# Generated by FakeRAM 2.0
VERSION 5.7 ;
BUSBITCHARS "[]" ;
PROPERTYDEFINITIONS
  MACRO width INTEGER ;
  MACRO depth INTEGER ;
  MACRO banks INTEGER ;
END PROPERTYDEFINITIONS
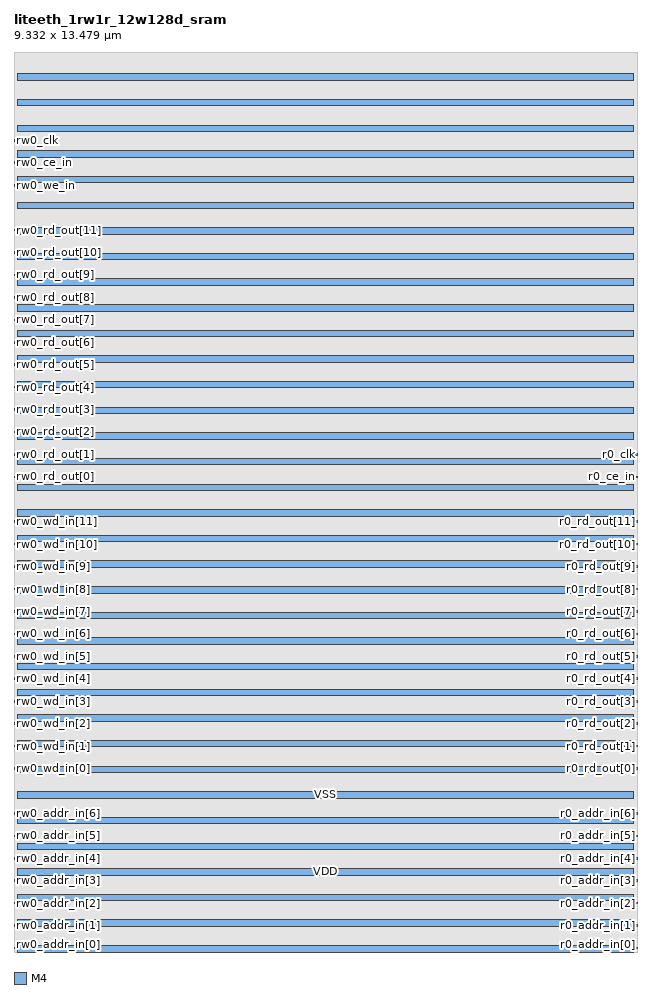
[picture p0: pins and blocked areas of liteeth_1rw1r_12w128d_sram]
MACRO liteeth_1rw1r_12w128d_sram
  PROPERTY width 12 ;
  PROPERTY depth 128 ;
  PROPERTY banks 1 ;
  FOREIGN liteeth_1rw1r_12w128d_sram 0 0 ;
  SYMMETRY X Y R90 ;
  SIZE 9.332 BY 13.479 ;
  CLASS BLOCK ;
  PIN r0_addr_in[0]
    DIRECTION INPUT ;
    USE SIGNAL ;
    SHAPE ABUTMENT ;
    PORT
      LAYER M4 ;
      RECT 9.308 0.048 9.332 0.072 ;
    END
  END r0_addr_in[0]
  PIN r0_addr_in[1]
    DIRECTION INPUT ;
    USE SIGNAL ;
    SHAPE ABUTMENT ;
    PORT
      LAYER M4 ;
      RECT 9.308 0.384 9.332 0.408 ;
    END
  END r0_addr_in[1]
  PIN r0_addr_in[2]
    DIRECTION INPUT ;
    USE SIGNAL ;
    SHAPE ABUTMENT ;
    PORT
      LAYER M4 ;
      RECT 9.308 0.720 9.332 0.744 ;
    END
  END r0_addr_in[2]
  PIN r0_addr_in[3]
    DIRECTION INPUT ;
    USE SIGNAL ;
    SHAPE ABUTMENT ;
    PORT
      LAYER M4 ;
      RECT 9.308 1.056 9.332 1.080 ;
    END
  END r0_addr_in[3]
  PIN r0_addr_in[4]
    DIRECTION INPUT ;
    USE SIGNAL ;
    SHAPE ABUTMENT ;
    PORT
      LAYER M4 ;
      RECT 9.308 1.392 9.332 1.416 ;
    END
  END r0_addr_in[4]
  PIN r0_addr_in[5]
    DIRECTION INPUT ;
    USE SIGNAL ;
    SHAPE ABUTMENT ;
    PORT
      LAYER M4 ;
      RECT 9.308 1.728 9.332 1.752 ;
    END
  END r0_addr_in[5]
  PIN r0_addr_in[6]
    DIRECTION INPUT ;
    USE SIGNAL ;
    SHAPE ABUTMENT ;
    PORT
      LAYER M4 ;
      RECT 9.308 2.064 9.332 2.088 ;
    END
  END r0_addr_in[6]
  PIN r0_rd_out[0]
    DIRECTION OUTPUT ;
    USE SIGNAL ;
    SHAPE ABUTMENT ;
    PORT
      LAYER M4 ;
      RECT 9.308 2.736 9.332 2.760 ;
    END
  END r0_rd_out[0]
  PIN r0_rd_out[1]
    DIRECTION OUTPUT ;
    USE SIGNAL ;
    SHAPE ABUTMENT ;
    PORT
      LAYER M4 ;
      RECT 9.308 3.072 9.332 3.096 ;
    END
  END r0_rd_out[1]
  PIN r0_rd_out[2]
    DIRECTION OUTPUT ;
    USE SIGNAL ;
    SHAPE ABUTMENT ;
    PORT
      LAYER M4 ;
      RECT 9.308 3.408 9.332 3.432 ;
    END
  END r0_rd_out[2]
  PIN r0_rd_out[3]
    DIRECTION OUTPUT ;
    USE SIGNAL ;
    SHAPE ABUTMENT ;
    PORT
      LAYER M4 ;
      RECT 9.308 3.744 9.332 3.768 ;
    END
  END r0_rd_out[3]
  PIN r0_rd_out[4]
    DIRECTION OUTPUT ;
    USE SIGNAL ;
    SHAPE ABUTMENT ;
    PORT
      LAYER M4 ;
      RECT 9.308 4.080 9.332 4.104 ;
    END
  END r0_rd_out[4]
  PIN r0_rd_out[5]
    DIRECTION OUTPUT ;
    USE SIGNAL ;
    SHAPE ABUTMENT ;
    PORT
      LAYER M4 ;
      RECT 9.308 4.416 9.332 4.440 ;
    END
  END r0_rd_out[5]
  PIN r0_rd_out[6]
    DIRECTION OUTPUT ;
    USE SIGNAL ;
    SHAPE ABUTMENT ;
    PORT
      LAYER M4 ;
      RECT 9.308 4.752 9.332 4.776 ;
    END
  END r0_rd_out[6]
  PIN r0_rd_out[7]
    DIRECTION OUTPUT ;
    USE SIGNAL ;
    SHAPE ABUTMENT ;
    PORT
      LAYER M4 ;
      RECT 9.308 5.088 9.332 5.112 ;
    END
  END r0_rd_out[7]
  PIN r0_rd_out[8]
    DIRECTION OUTPUT ;
    USE SIGNAL ;
    SHAPE ABUTMENT ;
    PORT
      LAYER M4 ;
      RECT 9.308 5.424 9.332 5.448 ;
    END
  END r0_rd_out[8]
  PIN r0_rd_out[9]
    DIRECTION OUTPUT ;
    USE SIGNAL ;
    SHAPE ABUTMENT ;
    PORT
      LAYER M4 ;
      RECT 9.308 5.760 9.332 5.784 ;
    END
  END r0_rd_out[9]
  PIN r0_rd_out[10]
    DIRECTION OUTPUT ;
    USE SIGNAL ;
    SHAPE ABUTMENT ;
    PORT
      LAYER M4 ;
      RECT 9.308 6.096 9.332 6.120 ;
    END
  END r0_rd_out[10]
  PIN r0_rd_out[11]
    DIRECTION OUTPUT ;
    USE SIGNAL ;
    SHAPE ABUTMENT ;
    PORT
      LAYER M4 ;
      RECT 9.308 6.432 9.332 6.456 ;
    END
  END r0_rd_out[11]
  PIN r0_ce_in
    DIRECTION INPUT ;
    USE SIGNAL ;
    SHAPE ABUTMENT ;
    PORT
      LAYER M4 ;
      RECT 9.308 7.104 9.332 7.128 ;
    END
  END r0_ce_in
  PIN r0_clk
    DIRECTION INPUT ;
    USE SIGNAL ;
    SHAPE ABUTMENT ;
    PORT
      LAYER M4 ;
      RECT 9.308 7.440 9.332 7.464 ;
    END
  END r0_clk
  PIN rw0_addr_in[0]
    DIRECTION INPUT ;
    USE SIGNAL ;
    SHAPE ABUTMENT ;
    PORT
      LAYER M4 ;
      RECT 0.000 0.048 0.024 0.072 ;
    END
  END rw0_addr_in[0]
  PIN rw0_addr_in[1]
    DIRECTION INPUT ;
    USE SIGNAL ;
    SHAPE ABUTMENT ;
    PORT
      LAYER M4 ;
      RECT 0.000 0.384 0.024 0.408 ;
    END
  END rw0_addr_in[1]
  PIN rw0_addr_in[2]
    DIRECTION INPUT ;
    USE SIGNAL ;
    SHAPE ABUTMENT ;
    PORT
      LAYER M4 ;
      RECT 0.000 0.720 0.024 0.744 ;
    END
  END rw0_addr_in[2]
  PIN rw0_addr_in[3]
    DIRECTION INPUT ;
    USE SIGNAL ;
    SHAPE ABUTMENT ;
    PORT
      LAYER M4 ;
      RECT 0.000 1.056 0.024 1.080 ;
    END
  END rw0_addr_in[3]
  PIN rw0_addr_in[4]
    DIRECTION INPUT ;
    USE SIGNAL ;
    SHAPE ABUTMENT ;
    PORT
      LAYER M4 ;
      RECT 0.000 1.392 0.024 1.416 ;
    END
  END rw0_addr_in[4]
  PIN rw0_addr_in[5]
    DIRECTION INPUT ;
    USE SIGNAL ;
    SHAPE ABUTMENT ;
    PORT
      LAYER M4 ;
      RECT 0.000 1.728 0.024 1.752 ;
    END
  END rw0_addr_in[5]
  PIN rw0_addr_in[6]
    DIRECTION INPUT ;
    USE SIGNAL ;
    SHAPE ABUTMENT ;
    PORT
      LAYER M4 ;
      RECT 0.000 2.064 0.024 2.088 ;
    END
  END rw0_addr_in[6]
  PIN rw0_wd_in[0]
    DIRECTION INPUT ;
    USE SIGNAL ;
    SHAPE ABUTMENT ;
    PORT
      LAYER M4 ;
      RECT 0.000 2.736 0.024 2.760 ;
    END
  END rw0_wd_in[0]
  PIN rw0_wd_in[1]
    DIRECTION INPUT ;
    USE SIGNAL ;
    SHAPE ABUTMENT ;
    PORT
      LAYER M4 ;
      RECT 0.000 3.072 0.024 3.096 ;
    END
  END rw0_wd_in[1]
  PIN rw0_wd_in[2]
    DIRECTION INPUT ;
    USE SIGNAL ;
    SHAPE ABUTMENT ;
    PORT
      LAYER M4 ;
      RECT 0.000 3.408 0.024 3.432 ;
    END
  END rw0_wd_in[2]
  PIN rw0_wd_in[3]
    DIRECTION INPUT ;
    USE SIGNAL ;
    SHAPE ABUTMENT ;
    PORT
      LAYER M4 ;
      RECT 0.000 3.744 0.024 3.768 ;
    END
  END rw0_wd_in[3]
  PIN rw0_wd_in[4]
    DIRECTION INPUT ;
    USE SIGNAL ;
    SHAPE ABUTMENT ;
    PORT
      LAYER M4 ;
      RECT 0.000 4.080 0.024 4.104 ;
    END
  END rw0_wd_in[4]
  PIN rw0_wd_in[5]
    DIRECTION INPUT ;
    USE SIGNAL ;
    SHAPE ABUTMENT ;
    PORT
      LAYER M4 ;
      RECT 0.000 4.416 0.024 4.440 ;
    END
  END rw0_wd_in[5]
  PIN rw0_wd_in[6]
    DIRECTION INPUT ;
    USE SIGNAL ;
    SHAPE ABUTMENT ;
    PORT
      LAYER M4 ;
      RECT 0.000 4.752 0.024 4.776 ;
    END
  END rw0_wd_in[6]
  PIN rw0_wd_in[7]
    DIRECTION INPUT ;
    USE SIGNAL ;
    SHAPE ABUTMENT ;
    PORT
      LAYER M4 ;
      RECT 0.000 5.088 0.024 5.112 ;
    END
  END rw0_wd_in[7]
  PIN rw0_wd_in[8]
    DIRECTION INPUT ;
    USE SIGNAL ;
    SHAPE ABUTMENT ;
    PORT
      LAYER M4 ;
      RECT 0.000 5.424 0.024 5.448 ;
    END
  END rw0_wd_in[8]
  PIN rw0_wd_in[9]
    DIRECTION INPUT ;
    USE SIGNAL ;
    SHAPE ABUTMENT ;
    PORT
      LAYER M4 ;
      RECT 0.000 5.760 0.024 5.784 ;
    END
  END rw0_wd_in[9]
  PIN rw0_wd_in[10]
    DIRECTION INPUT ;
    USE SIGNAL ;
    SHAPE ABUTMENT ;
    PORT
      LAYER M4 ;
      RECT 0.000 6.096 0.024 6.120 ;
    END
  END rw0_wd_in[10]
  PIN rw0_wd_in[11]
    DIRECTION INPUT ;
    USE SIGNAL ;
    SHAPE ABUTMENT ;
    PORT
      LAYER M4 ;
      RECT 0.000 6.432 0.024 6.456 ;
    END
  END rw0_wd_in[11]
  PIN rw0_rd_out[0]
    DIRECTION OUTPUT ;
    USE SIGNAL ;
    SHAPE ABUTMENT ;
    PORT
      LAYER M4 ;
      RECT 0.000 7.104 0.024 7.128 ;
    END
  END rw0_rd_out[0]
  PIN rw0_rd_out[1]
    DIRECTION OUTPUT ;
    USE SIGNAL ;
    SHAPE ABUTMENT ;
    PORT
      LAYER M4 ;
      RECT 0.000 7.440 0.024 7.464 ;
    END
  END rw0_rd_out[1]
  PIN rw0_rd_out[2]
    DIRECTION OUTPUT ;
    USE SIGNAL ;
    SHAPE ABUTMENT ;
    PORT
      LAYER M4 ;
      RECT 0.000 7.776 0.024 7.800 ;
    END
  END rw0_rd_out[2]
  PIN rw0_rd_out[3]
    DIRECTION OUTPUT ;
    USE SIGNAL ;
    SHAPE ABUTMENT ;
    PORT
      LAYER M4 ;
      RECT 0.000 8.112 0.024 8.136 ;
    END
  END rw0_rd_out[3]
  PIN rw0_rd_out[4]
    DIRECTION OUTPUT ;
    USE SIGNAL ;
    SHAPE ABUTMENT ;
    PORT
      LAYER M4 ;
      RECT 0.000 8.448 0.024 8.472 ;
    END
  END rw0_rd_out[4]
  PIN rw0_rd_out[5]
    DIRECTION OUTPUT ;
    USE SIGNAL ;
    SHAPE ABUTMENT ;
    PORT
      LAYER M4 ;
      RECT 0.000 8.784 0.024 8.808 ;
    END
  END rw0_rd_out[5]
  PIN rw0_rd_out[6]
    DIRECTION OUTPUT ;
    USE SIGNAL ;
    SHAPE ABUTMENT ;
    PORT
      LAYER M4 ;
      RECT 0.000 9.120 0.024 9.144 ;
    END
  END rw0_rd_out[6]
  PIN rw0_rd_out[7]
    DIRECTION OUTPUT ;
    USE SIGNAL ;
    SHAPE ABUTMENT ;
    PORT
      LAYER M4 ;
      RECT 0.000 9.456 0.024 9.480 ;
    END
  END rw0_rd_out[7]
  PIN rw0_rd_out[8]
    DIRECTION OUTPUT ;
    USE SIGNAL ;
    SHAPE ABUTMENT ;
    PORT
      LAYER M4 ;
      RECT 0.000 9.792 0.024 9.816 ;
    END
  END rw0_rd_out[8]
  PIN rw0_rd_out[9]
    DIRECTION OUTPUT ;
    USE SIGNAL ;
    SHAPE ABUTMENT ;
    PORT
      LAYER M4 ;
      RECT 0.000 10.128 0.024 10.152 ;
    END
  END rw0_rd_out[9]
  PIN rw0_rd_out[10]
    DIRECTION OUTPUT ;
    USE SIGNAL ;
    SHAPE ABUTMENT ;
    PORT
      LAYER M4 ;
      RECT 0.000 10.464 0.024 10.488 ;
    END
  END rw0_rd_out[10]
  PIN rw0_rd_out[11]
    DIRECTION OUTPUT ;
    USE SIGNAL ;
    SHAPE ABUTMENT ;
    PORT
      LAYER M4 ;
      RECT 0.000 10.800 0.024 10.824 ;
    END
  END rw0_rd_out[11]
  PIN rw0_we_in
    DIRECTION INPUT ;
    USE SIGNAL ;
    SHAPE ABUTMENT ;
    PORT
      LAYER M4 ;
      RECT 0.000 11.472 0.024 11.496 ;
    END
  END rw0_we_in
  PIN rw0_ce_in
    DIRECTION INPUT ;
    USE SIGNAL ;
    SHAPE ABUTMENT ;
    PORT
      LAYER M4 ;
      RECT 0.000 11.808 0.024 11.832 ;
    END
  END rw0_ce_in
  PIN rw0_clk
    DIRECTION INPUT ;
    USE SIGNAL ;
    SHAPE ABUTMENT ;
    PORT
      LAYER M4 ;
      RECT 0.000 12.144 0.024 12.168 ;
    END
  END rw0_clk
  PIN VSS
    DIRECTION INOUT ;
    USE GROUND ;
    PORT
      LAYER M4 ;
      RECT 0.048 0.000 9.284 0.096 ;
      RECT 0.048 0.768 9.284 0.864 ;
      RECT 0.048 1.536 9.284 1.632 ;
      RECT 0.048 2.304 9.284 2.400 ;
      RECT 0.048 3.072 9.284 3.168 ;
      RECT 0.048 3.840 9.284 3.936 ;
      RECT 0.048 4.608 9.284 4.704 ;
      RECT 0.048 5.376 9.284 5.472 ;
      RECT 0.048 6.144 9.284 6.240 ;
      RECT 0.048 6.912 9.284 7.008 ;
      RECT 0.048 7.680 9.284 7.776 ;
      RECT 0.048 8.448 9.284 8.544 ;
      RECT 0.048 9.216 9.284 9.312 ;
      RECT 0.048 9.984 9.284 10.080 ;
      RECT 0.048 10.752 9.284 10.848 ;
      RECT 0.048 11.520 9.284 11.616 ;
      RECT 0.048 12.288 9.284 12.384 ;
      RECT 0.048 13.056 9.284 13.152 ;
    END
  END VSS
  PIN VDD
    DIRECTION INOUT ;
    USE POWER ;
    PORT
      LAYER M4 ;
      RECT 0.048 0.384 9.284 0.480 ;
      RECT 0.048 1.152 9.284 1.248 ;
      RECT 0.048 1.920 9.284 2.016 ;
      RECT 0.048 2.688 9.284 2.784 ;
      RECT 0.048 3.456 9.284 3.552 ;
      RECT 0.048 4.224 9.284 4.320 ;
      RECT 0.048 4.992 9.284 5.088 ;
      RECT 0.048 5.760 9.284 5.856 ;
      RECT 0.048 6.528 9.284 6.624 ;
      RECT 0.048 7.296 9.284 7.392 ;
      RECT 0.048 8.064 9.284 8.160 ;
      RECT 0.048 8.832 9.284 8.928 ;
      RECT 0.048 9.600 9.284 9.696 ;
      RECT 0.048 10.368 9.284 10.464 ;
      RECT 0.048 11.136 9.284 11.232 ;
      RECT 0.048 11.904 9.284 12.000 ;
      RECT 0.048 12.672 9.284 12.768 ;
    END
  END VDD
  OBS
    LAYER M1 ;
    RECT 0 0 9.332 13.479 ;
    LAYER M2 ;
    RECT 0 0 9.332 13.479 ;
    LAYER M3 ;
    RECT 0 0 9.332 13.479 ;
    LAYER M4 ;
    RECT 0 0 9.332 13.479 ;
  END
END liteeth_1rw1r_12w128d_sram

END LIBRARY
